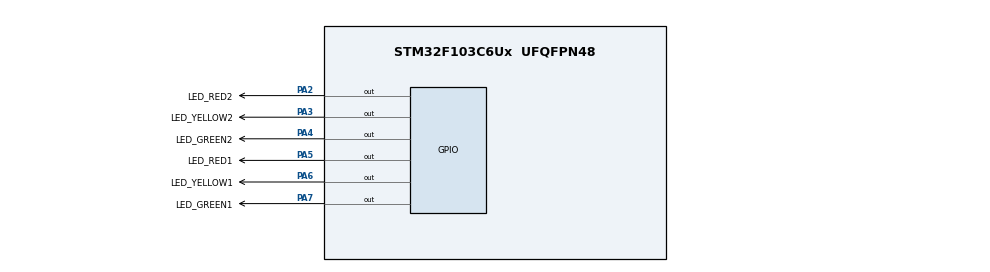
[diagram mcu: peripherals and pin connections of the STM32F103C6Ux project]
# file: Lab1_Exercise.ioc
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Mcu.Family=STM32F1
Mcu.Name=STM32F103C6Ux
Mcu.Package=UFQFPN48
NVIC.PriorityGroup=NVIC_PRIORITYGROUP_4
PA2.GPIO_Label=LED_RED2
PA2.Signal=GPIO_Output
PA3.GPIO_Label=LED_YELLOW2
PA3.Signal=GPIO_Output
PA4.GPIO_Label=LED_GREEN2
PA4.Signal=GPIO_Output
PA5.GPIO_Label=LED_RED1
PA5.Signal=GPIO_Output
PA6.GPIO_Label=LED_YELLOW1
PA6.Signal=GPIO_Output
PA7.GPIO_Label=LED_GREEN1
PA7.Signal=GPIO_Output
ProjectManager.HeapSize=0x200
ProjectManager.StackSize=0x400
ProjectManager.TargetToolchain=STM32CubeIDE
RCC.APB1Freq_Value=8000000
RCC.APB2Freq_Value=8000000
board=custom

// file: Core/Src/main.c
/* USER CODE BEGIN Header */
/**
  ******************************************************************************
  * @file           : main.c
  * @brief          : Main program body
  ******************************************************************************
  * @attention
  *
  * Copyright (c) 2023 STMicroelectronics.
  * All rights reserved.
  *
  * This software is licensed under terms that can be found in the LICENSE file
  * in the root directory of this software component.
  * If no LICENSE file comes with this software, it is provided AS-IS.
  *
  ******************************************************************************
  */
/* USER CODE END Header */
#include "main.h"

void SystemClock_Config(void);
static void MX_GPIO_Init(void);

/* USER CODE BEGIN 0 */
char AnodeNumber[] = {0xC0,0xF9,0xA4,0xB0,0x99,0x92,0x82,0x8f,0x80,0x90,0x80}; //0 - 9,dp

void display7SEG(int num) {
	HAL_GPIO_WritePin(LED7SEG_A_GPIO_Port, LED7SEG_A_Pin, AnodeNumber[num]&0x01?SET:RESET);
	HAL_GPIO_WritePin(LED7SEG_B_GPIO_Port, LED7SEG_B_Pin, AnodeNumber[num]&0x02?SET:RESET);
	HAL_GPIO_WritePin(LED7SEG_C_GPIO_Port, LED7SEG_C_Pin, AnodeNumber[num]&0x04?SET:RESET);
	HAL_GPIO_WritePin(LED7SEG_D_GPIO_Port, LED7SEG_D_Pin, AnodeNumber[num]&0x08?SET:RESET);
	HAL_GPIO_WritePin(LED7SEG_E_GPIO_Port, LED7SEG_E_Pin, AnodeNumber[num]&0x10?SET:RESET);
	HAL_GPIO_WritePin(LED7SEG_F_GPIO_Port, LED7SEG_F_Pin, AnodeNumber[num]&0x20?SET:RESET);
	HAL_GPIO_WritePin(LED7SEG_G_GPIO_Port, LED7SEG_G_Pin, AnodeNumber[num]&0x40?SET:RESET);

}

/* USER CODE END 0 */

int main(void)
{

  /* MCU Configuration--------------------------------------------------------*/

  /* Reset of all peripherals, Initializes the Flash interface and the Systick. */
  HAL_Init();

  /* Configure the system clock */
  SystemClock_Config();

  /* Initialize all configured peripherals */
  MX_GPIO_Init();

  /* Infinite loop */
  /* USER CODE BEGIN WHILE */

	void setLedOnWay1(char *led) {
	  HAL_GPIO_WritePin(LED_RED1_GPIO_Port, LED_RED1_Pin, led=="RED"?RESET:SET);
	  HAL_GPIO_WritePin(LED_YELLOW1_GPIO_Port, LED_YELLOW1_Pin, led=="YELLOW"?RESET:SET);
	  HAL_GPIO_WritePin(LED_GREEN1_GPIO_Port, LED_GREEN1_Pin, led=="GREEN"?RESET:SET);
	}
	void setLedOnWay2(char *led) {
	  HAL_GPIO_WritePin(LED_RED2_GPIO_Port, LED_RED2_Pin, led=="RED"?RESET:SET);
	  HAL_GPIO_WritePin(LED_YELLOW2_GPIO_Port, LED_YELLOW2_Pin, led=="YELLOW"?RESET:SET);
	  HAL_GPIO_WritePin(LED_GREEN2_GPIO_Port, LED_GREEN2_Pin, led=="GREEN"?RESET:SET);
	}

	int count1 = 500, count2 = 300, display_mode = 0;
	int state = 0;
	   while (1)
	   {
		   HAL_GPIO_WritePin(LED7SEG_EN_1_GPIO_Port, LED7SEG_EN_1_Pin, SET);
		   HAL_GPIO_WritePin(LED7SEG_EN_2_GPIO_Port, LED7SEG_EN_2_Pin, SET);

		  switch(state) {
		  case 0:					//RED1_GREEN2 : 3s
			  setLedOnWay1("RED");
			  setLedOnWay2("GREEN");
			  if(count2 <=0) {
				  state = 1;
				  count2 = 200;
			  }
			  break;
		  case 1:					//RED1_YELLOW2 : 2s
			  setLedOnWay1("RED");
			  setLedOnWay2("YELLOW");
			  if(count1 <=0) {
				  state = 2;
				  count1 = 300;
				  count2 = 500;
			  }
			  break;
		  case 2:					//GREEN1_RED2 : 3s
			  setLedOnWay1("GREEN");
			  setLedOnWay2("RED");
			  if(count1 <=0) {
				  state = 3;
				  count1 = 200;
			  }
			  break;
		  case 3:					//YELLOW1_RED2 : 2s
			  setLedOnWay1("YELLOW");
			  setLedOnWay2("RED");
			  if(count2 <=0) {
				  state = 0;
				  count1 = 500;
				  count2 = 300;
			  }
			  break;
		  }
		  if(display_mode == 1) {
			  display7SEG(count1/100);
			  HAL_GPIO_WritePin(LED7SEG_EN_1_GPIO_Port, LED7SEG_EN_1_Pin, RESET);
		  }
		  else {
				display7SEG(count2/100);
				HAL_GPIO_WritePin(LED7SEG_EN_2_GPIO_Port, LED7SEG_EN_2_Pin, RESET);
			}

  		 count2--;
  	  	 count1--;
  	  	 display_mode = 1-display_mode;
  	  	 HAL_Delay(10);
    /* USER CODE END WHILE */

  }
}

void SystemClock_Config(void)
{
  RCC_OscInitTypeDef RCC_OscInitStruct = {0};
  RCC_ClkInitTypeDef RCC_ClkInitStruct = {0};

  /** Initializes the RCC Oscillators according to the specified parameters
  * in the RCC_OscInitTypeDef structure.
  */
  RCC_OscInitStruct.OscillatorType = RCC_OSCILLATORTYPE_HSI;
  RCC_OscInitStruct.HSIState = RCC_HSI_ON;
  RCC_OscInitStruct.HSICalibrationValue = RCC_HSICALIBRATION_DEFAULT;
  RCC_OscInitStruct.PLL.PLLState = RCC_PLL_NONE;
  if (HAL_RCC_OscConfig(&RCC_OscInitStruct) != HAL_OK)
  {
    Error_Handler();
  }

  /** Initializes the CPU, AHB and APB buses clocks
  */
  RCC_ClkInitStruct.ClockType = RCC_CLOCKTYPE_HCLK|RCC_CLOCKTYPE_SYSCLK
                              |RCC_CLOCKTYPE_PCLK1|RCC_CLOCKTYPE_PCLK2;
  RCC_ClkInitStruct.SYSCLKSource = RCC_SYSCLKSOURCE_HSI;
  RCC_ClkInitStruct.AHBCLKDivider = RCC_SYSCLK_DIV1;
  RCC_ClkInitStruct.APB1CLKDivider = RCC_HCLK_DIV1;
  RCC_ClkInitStruct.APB2CLKDivider = RCC_HCLK_DIV1;

  if (HAL_RCC_ClockConfig(&RCC_ClkInitStruct, FLASH_LATENCY_0) != HAL_OK)
  {
    Error_Handler();
  }
}

static void MX_GPIO_Init(void)
{
  GPIO_InitTypeDef GPIO_InitStruct = {0};

  /* GPIO Ports Clock Enable */
  __HAL_RCC_GPIOA_CLK_ENABLE();
  __HAL_RCC_GPIOB_CLK_ENABLE();

  /*Configure GPIO pin Output Level */
  HAL_GPIO_WritePin(GPIOA, LED_RED2_Pin|LED_YELLOW2_Pin|LED_YELLOW1_Pin|LED_GREEN1_Pin
                          |LED7SEG_EN_2_Pin, GPIO_PIN_RESET);

  /*Configure GPIO pin Output Level */
  HAL_GPIO_WritePin(GPIOA, LED_GREEN2_Pin|LED_RED1_Pin, GPIO_PIN_SET);

  /*Configure GPIO pin Output Level */
  HAL_GPIO_WritePin(GPIOB, LED7SEG_A_Pin|LED7SEG_B_Pin|LED7SEG_C_Pin|LED7SEG_EN_1_Pin
                          |LED7SEG_D_Pin|LED7SEG_E_Pin|LED7SEG_F_Pin|LED7SEG_G_Pin, GPIO_PIN_RESET);

  /*Configure GPIO pins : LED_RED2_Pin LED_YELLOW2_Pin LED_GREEN2_Pin LED_RED1_Pin
                           LED_YELLOW1_Pin LED_GREEN1_Pin LED7SEG_EN_2_Pin */
  GPIO_InitStruct.Pin = LED_RED2_Pin|LED_YELLOW2_Pin|LED_GREEN2_Pin|LED_RED1_Pin
                          |LED_YELLOW1_Pin|LED_GREEN1_Pin|LED7SEG_EN_2_Pin;
  GPIO_InitStruct.Mode = GPIO_MODE_OUTPUT_PP;
  GPIO_InitStruct.Pull = GPIO_NOPULL;
  GPIO_InitStruct.Speed = GPIO_SPEED_FREQ_LOW;
  HAL_GPIO_Init(GPIOA, &GPIO_InitStruct);

  /*Configure GPIO pins : LED7SEG_A_Pin LED7SEG_B_Pin LED7SEG_C_Pin LED7SEG_EN_1_Pin
                           LED7SEG_D_Pin LED7SEG_E_Pin LED7SEG_F_Pin LED7SEG_G_Pin */
  GPIO_InitStruct.Pin = LED7SEG_A_Pin|LED7SEG_B_Pin|LED7SEG_C_Pin|LED7SEG_EN_1_Pin
                          |LED7SEG_D_Pin|LED7SEG_E_Pin|LED7SEG_F_Pin|LED7SEG_G_Pin;
  GPIO_InitStruct.Mode = GPIO_MODE_OUTPUT_PP;
  GPIO_InitStruct.Pull = GPIO_NOPULL;
  GPIO_InitStruct.Speed = GPIO_SPEED_FREQ_LOW;
  HAL_GPIO_Init(GPIOB, &GPIO_InitStruct);

}

void Error_Handler(void)
{
  __disable_irq();
  while (1)
  {
  }
}
